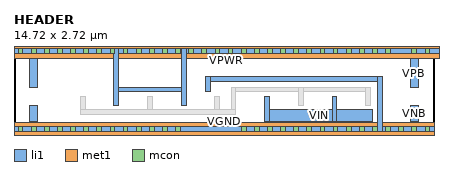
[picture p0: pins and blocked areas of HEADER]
MACRO HEADER
  CLASS CORE ;
  ORIGIN 0 0 ;
  FOREIGN HEADER 0 0 ;
  SIZE 14.72 BY 2.72 ;
  SYMMETRY X Y ;
  SITE unithd ;
  PIN VIN
    DIRECTION INPUT ;
    USE SIGNAL ;
    PORT
      LAYER li1 ;
        RECT 8.79 0.255 12.56 0.67 ;
        RECT 11.15 0.255 11.32 1.13 ;
        RECT 8.79 0.255 8.96 1.13 ;
    END
  END VIN
  PIN VNB
    DIRECTION INOUT ;
    USE GROUND ;
    PORT
      LAYER li1 ;
        RECT 13.885 0.265 14.175 0.81 ;
        RECT 0.545 0.265 0.835 0.81 ;
    END
  END VNB
  PIN VPB
    DIRECTION INOUT ;
    USE POWER ;
    PORT
      LAYER li1 ;
        RECT 13.885 1.47 14.175 2.455 ;
        RECT 0.545 1.47 0.835 2.455 ;
    END
  END VPB
  PIN VPWR
    DIRECTION INOUT ;
    USE POWER ;
    PORT
      LAYER met1 ;
        RECT 0 2.48 14.91 2.96 ;
      LAYER li1 ;
        RECT 0 2.635 14.91 2.805 ;
        RECT 5.86 0.84 6.03 2.805 ;
        RECT 3.495 1.3 6.03 1.47 ;
        RECT 3.495 0.84 3.665 2.805 ;
      LAYER mcon ;
        RECT 0.145 2.635 0.315 2.805 ;
        RECT 0.605 2.635 0.775 2.805 ;
        RECT 1.065 2.635 1.235 2.805 ;
        RECT 1.525 2.635 1.695 2.805 ;
        RECT 1.985 2.635 2.155 2.805 ;
        RECT 2.445 2.635 2.615 2.805 ;
        RECT 2.905 2.635 3.075 2.805 ;
        RECT 3.365 2.635 3.535 2.805 ;
        RECT 3.825 2.635 3.995 2.805 ;
        RECT 4.285 2.635 4.455 2.805 ;
        RECT 4.745 2.635 4.915 2.805 ;
        RECT 5.205 2.635 5.375 2.805 ;
        RECT 5.665 2.635 5.835 2.805 ;
        RECT 6.125 2.635 6.295 2.805 ;
        RECT 6.585 2.635 6.755 2.805 ;
        RECT 7.045 2.635 7.215 2.805 ;
        RECT 7.505 2.635 7.675 2.805 ;
        RECT 7.965 2.635 8.135 2.805 ;
        RECT 8.425 2.635 8.595 2.805 ;
        RECT 8.885 2.635 9.055 2.805 ;
        RECT 9.345 2.635 9.515 2.805 ;
        RECT 9.805 2.635 9.975 2.805 ;
        RECT 10.265 2.635 10.435 2.805 ;
        RECT 10.725 2.635 10.895 2.805 ;
        RECT 11.185 2.635 11.355 2.805 ;
        RECT 11.645 2.635 11.815 2.805 ;
        RECT 12.105 2.635 12.275 2.805 ;
        RECT 12.565 2.635 12.735 2.805 ;
        RECT 13.025 2.635 13.195 2.805 ;
        RECT 13.945 2.635 14.115 2.805 ;
        RECT 14.405 2.635 14.575 2.805 ;
    END
  END VPWR
  PIN VGND
    DIRECTION INOUT ;
    USE GROUND ;
    PORT
      LAYER met1 ;
        RECT 0 -0.24 14.72 0.24 ;
      LAYER li1 ;
        RECT 0 -0.085 14.72 0.085 ;
        RECT 6.715 1.68 12.9 1.85 ;
        RECT 12.73 -0.085 12.9 1.85 ;
        RECT 6.715 1.3 6.885 1.85 ;
      LAYER mcon ;
        RECT 0.145 -0.085 0.315 0.085 ;
        RECT 0.605 -0.085 0.775 0.085 ;
        RECT 1.065 -0.085 1.235 0.085 ;
        RECT 1.525 -0.085 1.695 0.085 ;
        RECT 1.985 -0.085 2.155 0.085 ;
        RECT 2.445 -0.085 2.615 0.085 ;
        RECT 2.905 -0.085 3.075 0.085 ;
        RECT 3.365 -0.085 3.535 0.085 ;
        RECT 3.825 -0.085 3.995 0.085 ;
        RECT 4.285 -0.085 4.455 0.085 ;
        RECT 4.745 -0.085 4.915 0.085 ;
        RECT 5.205 -0.085 5.375 0.085 ;
        RECT 5.665 -0.085 5.835 0.085 ;
        RECT 7.965 -0.085 8.135 0.085 ;
        RECT 8.425 -0.085 8.595 0.085 ;
        RECT 8.885 -0.085 9.055 0.085 ;
        RECT 9.345 -0.085 9.515 0.085 ;
        RECT 9.805 -0.085 9.975 0.085 ;
        RECT 10.265 -0.085 10.435 0.085 ;
        RECT 10.725 -0.085 10.895 0.085 ;
        RECT 11.185 -0.085 11.355 0.085 ;
        RECT 11.645 -0.085 11.815 0.085 ;
        RECT 12.105 -0.085 12.275 0.085 ;
        RECT 12.565 -0.085 12.735 0.085 ;
        RECT 13.025 -0.085 13.195 0.085 ;
        RECT 13.485 -0.085 13.655 0.085 ;
        RECT 13.945 -0.085 14.115 0.085 ;
        RECT 14.405 -0.085 14.575 0.085 ;
    END
  END VGND
  OBS
    LAYER li1 ;
      RECT 7.61 1.3 12.5 1.47 ;
      RECT 12.33 0.84 12.5 1.47 ;
      RECT 9.97 0.84 10.14 1.47 ;
      RECT 7.61 0.5 7.78 1.47 ;
      RECT 7.04 0.5 7.21 1.13 ;
      RECT 4.68 0.5 4.85 1.13 ;
      RECT 2.32 0.5 2.49 1.13 ;
      RECT 7.04 0.5 7.78 0.675 ;
      RECT 2.32 0.5 7.78 0.67 ;
  END
END HEADER

END LIBRARY
